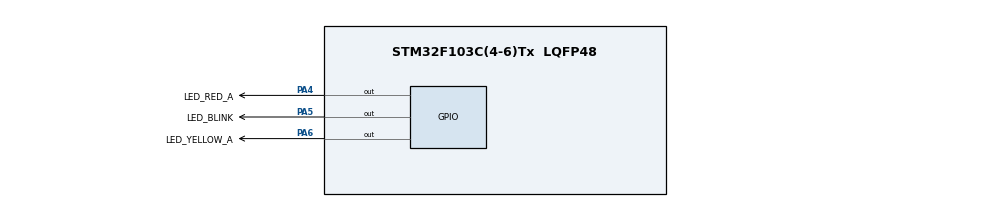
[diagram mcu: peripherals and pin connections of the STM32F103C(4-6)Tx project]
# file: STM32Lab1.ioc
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Mcu.Family=STM32F1
Mcu.Name=STM32F103C(4-6)Tx
Mcu.Package=LQFP48
NVIC.PriorityGroup=NVIC_PRIORITYGROUP_4
PA4.GPIO_Label=LED_RED_A
PA4.Signal=GPIO_Output
PA5.GPIO_Label=LED_BLINK
PA5.Signal=GPIO_Output
PA6.GPIO_Label=LED_YELLOW_A
PA6.Signal=GPIO_Output
ProjectManager.HeapSize=0x200
ProjectManager.StackSize=0x400
ProjectManager.TargetToolchain=STM32CubeIDE
RCC.APB1Freq_Value=8000000
RCC.APB2Freq_Value=8000000
VP_SYS_VS_ND.Mode=No_Debug
board=custom

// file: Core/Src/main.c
/* USER CODE BEGIN Header */
/**
  ******************************************************************************
  * @file           : main.c
  * @brief          : Main program body
  ******************************************************************************
  * @attention
  *
  * <h2><center>&copy; Copyright (c) 2025 STMicroelectronics.
  * All rights reserved.</center></h2>
  *
  * This software component is licensed by ST under BSD 3-Clause license,
  * the "License"; You may not use this file except in compliance with the
  * License. You may obtain a copy of the License at:
  *                        opensource.org/licenses/BSD-3-Clause
  *
  ******************************************************************************
  */
/* USER CODE END Header */
#include "main.h"

/* USER CODE BEGIN PV */
typedef enum {
    STATE_GREEN1_RED2,
    STATE_YELLOW1_RED2,
    STATE_RED1_GREEN2,
    STATE_RED1_YELLOW2
} TrafficState;

TrafficState state = STATE_GREEN1_RED2;
int timer = -1;
/* USER CODE END PV */

void SystemClock_Config(void);
static void MX_GPIO_Init(void);

/* USER CODE BEGIN 0 */
void clearAllLed(){
	HAL_GPIO_WritePin(LED_RED_A_GPIO_Port,     LED_RED_A_Pin,     GPIO_PIN_SET);
	HAL_GPIO_WritePin(LED_YELLOW_A_GPIO_Port,  LED_YELLOW_A_Pin,  GPIO_PIN_SET);
	HAL_GPIO_WritePin(LED_GREEN_A_GPIO_Port,   LED_GREEN_A_Pin,   GPIO_PIN_SET);

	HAL_GPIO_WritePin(LED_RED_B_GPIO_Port,     LED_RED_B_Pin,     GPIO_PIN_SET);
	HAL_GPIO_WritePin(LED_YELLOW_B_GPIO_Port,  LED_YELLOW_B_Pin,  GPIO_PIN_SET);
	HAL_GPIO_WritePin(LED_GREEN_B_GPIO_Port,   LED_GREEN_B_Pin,   GPIO_PIN_SET);

	HAL_GPIO_WritePin(LED_RED_C_GPIO_Port,     LED_RED_C_Pin,     GPIO_PIN_SET);
	HAL_GPIO_WritePin(LED_YELLOW_C_GPIO_Port,  LED_YELLOW_C_Pin,  GPIO_PIN_SET);
	HAL_GPIO_WritePin(LED_GREEN_C_GPIO_Port,   LED_GREEN_C_Pin,   GPIO_PIN_SET);

	HAL_GPIO_WritePin(LED_RED_D_GPIO_Port,     LED_RED_D_Pin,     GPIO_PIN_SET);
	HAL_GPIO_WritePin(LED_YELLOW_D_GPIO_Port,  LED_YELLOW_D_Pin,  GPIO_PIN_SET);
	HAL_GPIO_WritePin(LED_GREEN_D_GPIO_Port,   LED_GREEN_D_Pin,   GPIO_PIN_SET);
}

void displayDigit(int num) {
    switch (num) {
        case 0: // ABCDEF sáng, G tắt
            HAL_GPIO_WritePin(A_GPIO_Port, A_Pin, GPIO_PIN_RESET);
            HAL_GPIO_WritePin(B_GPIO_Port, B_Pin, GPIO_PIN_RESET);
            HAL_GPIO_WritePin(C_GPIO_Port, C_Pin, GPIO_PIN_RESET);
            HAL_GPIO_WritePin(D_GPIO_Port, D_Pin, GPIO_PIN_RESET);
            HAL_GPIO_WritePin(E_GPIO_Port, E_Pin, GPIO_PIN_RESET);
            HAL_GPIO_WritePin(F_GPIO_Port, F_Pin, GPIO_PIN_RESET);
            HAL_GPIO_WritePin(G_GPIO_Port, G_Pin, GPIO_PIN_SET);
            break;
        case 1: // BC sáng
            HAL_GPIO_WritePin(A_GPIO_Port, A_Pin, GPIO_PIN_SET);
            HAL_GPIO_WritePin(B_GPIO_Port, B_Pin, GPIO_PIN_RESET);
            HAL_GPIO_WritePin(C_GPIO_Port, C_Pin, GPIO_PIN_RESET);
            HAL_GPIO_WritePin(D_GPIO_Port, D_Pin, GPIO_PIN_SET);
            HAL_GPIO_WritePin(E_GPIO_Port, E_Pin, GPIO_PIN_SET);
            HAL_GPIO_WritePin(F_GPIO_Port, F_Pin, GPIO_PIN_SET);
            HAL_GPIO_WritePin(G_GPIO_Port, G_Pin, GPIO_PIN_SET);
            break;
        case 2: // ABDEG sáng
            HAL_GPIO_WritePin(A_GPIO_Port, A_Pin, GPIO_PIN_RESET);
            HAL_GPIO_WritePin(B_GPIO_Port, B_Pin, GPIO_PIN_RESET);
            HAL_GPIO_WritePin(C_GPIO_Port, C_Pin, GPIO_PIN_SET);
            HAL_GPIO_WritePin(D_GPIO_Port, D_Pin, GPIO_PIN_RESET);
            HAL_GPIO_WritePin(E_GPIO_Port, E_Pin, GPIO_PIN_RESET);
            HAL_GPIO_WritePin(F_GPIO_Port, F_Pin, GPIO_PIN_SET);
            HAL_GPIO_WritePin(G_GPIO_Port, G_Pin, GPIO_PIN_RESET);
            break;
        case 3: // ABCDG sáng
            HAL_GPIO_WritePin(A_GPIO_Port, A_Pin, GPIO_PIN_RESET);
            HAL_GPIO_WritePin(B_GPIO_Port, B_Pin, GPIO_PIN_RESET);
            HAL_GPIO_WritePin(C_GPIO_Port, C_Pin, GPIO_PIN_RESET);
            HAL_GPIO_WritePin(D_GPIO_Port, D_Pin, GPIO_PIN_RESET);
            HAL_GPIO_WritePin(E_GPIO_Port, E_Pin, GPIO_PIN_SET);
            HAL_GPIO_WritePin(F_GPIO_Port, F_Pin, GPIO_PIN_SET);
            HAL_GPIO_WritePin(G_GPIO_Port, G_Pin, GPIO_PIN_RESET);
            break;
        case 4: // BCFG sáng
            HAL_GPIO_WritePin(A_GPIO_Port, A_Pin, GPIO_PIN_SET);
            HAL_GPIO_WritePin(B_GPIO_Port, B_Pin, GPIO_PIN_RESET);
            HAL_GPIO_WritePin(C_GPIO_Port, C_Pin, GPIO_PIN_RESET);
            HAL_GPIO_WritePin(D_GPIO_Port, D_Pin, GPIO_PIN_SET);
            HAL_GPIO_WritePin(E_GPIO_Port, E_Pin, GPIO_PIN_SET);
            HAL_GPIO_WritePin(F_GPIO_Port, F_Pin, GPIO_PIN_RESET);
            HAL_GPIO_WritePin(G_GPIO_Port, G_Pin, GPIO_PIN_RESET);
            break;
        default: // tắt hết
            HAL_GPIO_WritePin(A_GPIO_Port, A_Pin, GPIO_PIN_SET);
            HAL_GPIO_WritePin(B_GPIO_Port, B_Pin, GPIO_PIN_SET);
            HAL_GPIO_WritePin(C_GPIO_Port, C_Pin, GPIO_PIN_SET);
            HAL_GPIO_WritePin(D_GPIO_Port, D_Pin, GPIO_PIN_SET);
            HAL_GPIO_WritePin(E_GPIO_Port, E_Pin, GPIO_PIN_SET);
            HAL_GPIO_WritePin(F_GPIO_Port, F_Pin, GPIO_PIN_SET);
            HAL_GPIO_WritePin(G_GPIO_Port, G_Pin, GPIO_PIN_SET);
            break;
    }
}

/* Ham chuyen den duong 1*/
void YellowToRed1(){
	HAL_GPIO_WritePin(GPIOA, LED_RED_A_Pin, GPIO_PIN_RESET);
	HAL_GPIO_WritePin(GPIOA, LED_YELLOW_A_Pin, GPIO_PIN_SET);
	HAL_GPIO_WritePin(GPIOA, LED_RED_C_Pin, GPIO_PIN_RESET);
	HAL_GPIO_WritePin(GPIOA, LED_YELLOW_C_Pin, GPIO_PIN_SET);
}
void RedToGreen1(){
	HAL_GPIO_WritePin(GPIOA, LED_RED_A_Pin, GPIO_PIN_SET);
	HAL_GPIO_WritePin(GPIOA, LED_GREEN_A_Pin, GPIO_PIN_RESET);
	HAL_GPIO_WritePin(GPIOA, LED_RED_C_Pin, GPIO_PIN_SET);
	HAL_GPIO_WritePin(GPIOA, LED_GREEN_C_Pin, GPIO_PIN_RESET);
}
void GreenToYellow1(){
	HAL_GPIO_WritePin(GPIOA, LED_GREEN_A_Pin, GPIO_PIN_SET);
	HAL_GPIO_WritePin(GPIOA, LED_YELLOW_A_Pin, GPIO_PIN_RESET);
	HAL_GPIO_WritePin(GPIOA, LED_GREEN_C_Pin, GPIO_PIN_SET);
	HAL_GPIO_WritePin(GPIOA, LED_YELLOW_C_Pin, GPIO_PIN_RESET);
}

/* Ham chuyen den duong 2*/
void YellowToRed2(){
	HAL_GPIO_WritePin(GPIOA, LED_RED_B_Pin, GPIO_PIN_RESET);
	HAL_GPIO_WritePin(GPIOA, LED_YELLOW_B_Pin, GPIO_PIN_SET);
	HAL_GPIO_WritePin(GPIOA, LED_RED_D_Pin, GPIO_PIN_RESET);
	HAL_GPIO_WritePin(GPIOA, LED_YELLOW_D_Pin, GPIO_PIN_SET);
}
void RedToGreen2(){
	HAL_GPIO_WritePin(GPIOA, LED_RED_B_Pin, GPIO_PIN_SET);
	HAL_GPIO_WritePin(GPIOA, LED_GREEN_B_Pin, GPIO_PIN_RESET);
	HAL_GPIO_WritePin(GPIOA, LED_RED_D_Pin, GPIO_PIN_SET);
	HAL_GPIO_WritePin(GPIOA, LED_GREEN_D_Pin, GPIO_PIN_RESET);
}
void GreenToYellow2(){
	HAL_GPIO_WritePin(GPIOA, LED_GREEN_B_Pin, GPIO_PIN_SET);
	HAL_GPIO_WritePin(GPIOA, LED_YELLOW_B_Pin, GPIO_PIN_RESET);
	HAL_GPIO_WritePin(GPIOA, LED_GREEN_D_Pin, GPIO_PIN_SET);
	HAL_GPIO_WritePin(GPIOA, LED_YELLOW_D_Pin, GPIO_PIN_RESET);
}

/* USER CODE END 0 */

int main(void)
{

  /* MCU Configuration--------------------------------------------------------*/

  /* Reset of all peripherals, Initializes the Flash interface and the Systick. */
  HAL_Init();

  /* Configure the system clock */
  SystemClock_Config();

  /* Initialize all configured peripherals */
  MX_GPIO_Init();
  /* USER CODE BEGIN 2 */
  clearAllLed();
  /* USER CODE END 2 */
  /* Infinite loop */
  /* USER CODE BEGIN WHILE */
  while (1)
  {
	  HAL_GPIO_TogglePin(GPIOA, LED_BLINK_Pin);

	  if(state == STATE_RED1_GREEN2 && timer == 1){
  		  GreenToYellow2();
  		  state = STATE_RED1_YELLOW2;
	  }
	  if(timer < 0){
		  switch(state){
		  	  case STATE_GREEN1_RED2:
		  		  GreenToYellow1();
		  		  YellowToRed2();
		  		  state = STATE_YELLOW1_RED2;
		  		  timer = 1;
		  		  break;
		  	  case STATE_YELLOW1_RED2:
		  		  YellowToRed1();
		  		  RedToGreen2();
		  		  state = STATE_RED1_GREEN2;
		  		  timer = 4;
		  		  break;
		  	  case STATE_RED1_YELLOW2:
		  		  RedToGreen1();
		  		  YellowToRed2();
		  		  state = STATE_GREEN1_RED2;
		  		  timer = 2;
		  		  break;
		  	  default:
		  		  break;
		  }
	  }

	  displayDigit(timer);
	  timer--;
	  HAL_Delay(1000);

    /* USER CODE END WHILE */

  }
}

void SystemClock_Config(void)
{
  RCC_OscInitTypeDef RCC_OscInitStruct = {0};
  RCC_ClkInitTypeDef RCC_ClkInitStruct = {0};

  /** Initializes the RCC Oscillators according to the specified parameters
  * in the RCC_OscInitTypeDef structure.
  */
  RCC_OscInitStruct.OscillatorType = RCC_OSCILLATORTYPE_HSI;
  RCC_OscInitStruct.HSIState = RCC_HSI_ON;
  RCC_OscInitStruct.HSICalibrationValue = RCC_HSICALIBRATION_DEFAULT;
  RCC_OscInitStruct.PLL.PLLState = RCC_PLL_NONE;
  if (HAL_RCC_OscConfig(&RCC_OscInitStruct) != HAL_OK)
  {
    Error_Handler();
  }
  /** Initializes the CPU, AHB and APB buses clocks
  */
  RCC_ClkInitStruct.ClockType = RCC_CLOCKTYPE_HCLK|RCC_CLOCKTYPE_SYSCLK
                              |RCC_CLOCKTYPE_PCLK1|RCC_CLOCKTYPE_PCLK2;
  RCC_ClkInitStruct.SYSCLKSource = RCC_SYSCLKSOURCE_HSI;
  RCC_ClkInitStruct.AHBCLKDivider = RCC_SYSCLK_DIV1;
  RCC_ClkInitStruct.APB1CLKDivider = RCC_HCLK_DIV1;
  RCC_ClkInitStruct.APB2CLKDivider = RCC_HCLK_DIV1;

  if (HAL_RCC_ClockConfig(&RCC_ClkInitStruct, FLASH_LATENCY_0) != HAL_OK)
  {
    Error_Handler();
  }
}

static void MX_GPIO_Init(void)
{
  GPIO_InitTypeDef GPIO_InitStruct = {0};

  /* GPIO Ports Clock Enable */
  __HAL_RCC_GPIOA_CLK_ENABLE();
  __HAL_RCC_GPIOB_CLK_ENABLE();

  /*Configure GPIO pin Output Level */
  HAL_GPIO_WritePin(GPIOA, LED_RED_A_Pin|LED_YELLOW_A_Pin|LED_GREEN_A_Pin|LED_RED_B_Pin
                          |LED_BLINK_Pin|LED_YELLOW_B_Pin|LED_GREEN_B_Pin|LED_RED_C_Pin
                          |LED_YELLOW_C_Pin|LED_GREEN_C_Pin|LED_RED_D_Pin|LED_YELLOW_D_Pin
                          |LED_GREEN_D_Pin, GPIO_PIN_RESET);

  /*Configure GPIO pin Output Level */
  HAL_GPIO_WritePin(GPIOB, A_Pin|B_Pin|C_Pin|D_Pin
                          |E_Pin|F_Pin|G_Pin, GPIO_PIN_RESET);

  /*Configure GPIO pins : LED_RED_A_Pin LED_YELLOW_A_Pin LED_GREEN_A_Pin LED_RED_B_Pin
                           LED_BLINK_Pin LED_YELLOW_B_Pin LED_GREEN_B_Pin LED_RED_C_Pin
                           LED_YELLOW_C_Pin LED_GREEN_C_Pin LED_RED_D_Pin LED_YELLOW_D_Pin
                           LED_GREEN_D_Pin */
  GPIO_InitStruct.Pin = LED_RED_A_Pin|LED_YELLOW_A_Pin|LED_GREEN_A_Pin|LED_RED_B_Pin
                          |LED_BLINK_Pin|LED_YELLOW_B_Pin|LED_GREEN_B_Pin|LED_RED_C_Pin
                          |LED_YELLOW_C_Pin|LED_GREEN_C_Pin|LED_RED_D_Pin|LED_YELLOW_D_Pin
                          |LED_GREEN_D_Pin;
  GPIO_InitStruct.Mode = GPIO_MODE_OUTPUT_PP;
  GPIO_InitStruct.Pull = GPIO_NOPULL;
  GPIO_InitStruct.Speed = GPIO_SPEED_FREQ_LOW;
  HAL_GPIO_Init(GPIOA, &GPIO_InitStruct);

  /*Configure GPIO pins : A_Pin B_Pin C_Pin D_Pin
                           E_Pin F_Pin G_Pin */
  GPIO_InitStruct.Pin = A_Pin|B_Pin|C_Pin|D_Pin
                          |E_Pin|F_Pin|G_Pin;
  GPIO_InitStruct.Mode = GPIO_MODE_OUTPUT_PP;
  GPIO_InitStruct.Pull = GPIO_NOPULL;
  GPIO_InitStruct.Speed = GPIO_SPEED_FREQ_LOW;
  HAL_GPIO_Init(GPIOB, &GPIO_InitStruct);

}

void Error_Handler(void)
{
  __disable_irq();
  while (1)
  {
  }
}

/************************ (C) COPYRIGHT STMicroelectronics *****END OF FILE****/
